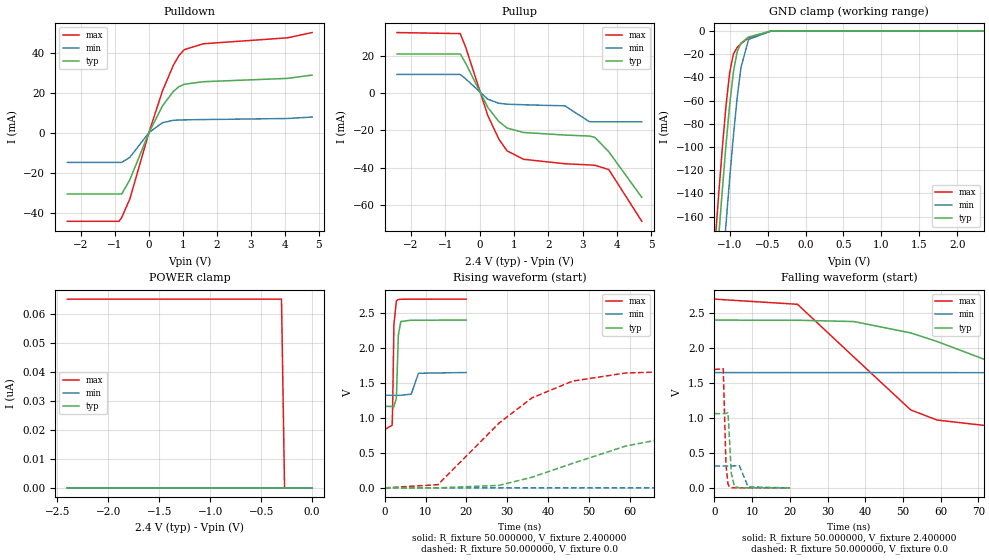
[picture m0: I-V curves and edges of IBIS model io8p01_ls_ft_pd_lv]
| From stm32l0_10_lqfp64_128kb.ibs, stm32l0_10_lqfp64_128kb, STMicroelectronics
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|   Model io8p01_ls_ft_pd_lv
[Model]  io8p01_ls_ft_pd_lv
Model_type I/O
Polarity   Non-Inverting
Enable   Active-Low
Vinl =   0.720000V
Vinh =   1.680000V
Vmeas =  1.200000V
Cref =   50.000000pF
Rref =   100.000000M
Vref =   0.0V
C_comp   4.521100pF   4.438000pF   4.578000pF
[Temperature Range]   25.000000   0.105000k   -40.000000
[Pullup Reference]   2.400000V   1.650000V   2.700000V
[Pulldown Reference]   0.0V   0.0V   0.0V
[POWER Clamp Reference]   2.400000V   1.650000V   2.700000V
[GND Clamp Reference]   0.0V   0.0V   0.0V
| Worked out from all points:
|   slope of the pulldown table from 0 to 0.36 V, typ, clamps not added: 29.5 ohm
|   slope of the pullup table from 0 to 0.36 V, typ, clamps not added: 33.2 ohm
|   GND clamp passes 1 mA (typ) near -0.59 V on its own axis
|   rising waveform, R_fixture 50.000000, V_fixture 2.400000: 20-80 % time 359ps typ, 683ps min, 299ps max; typ from 1.17 V to 2.4 V
|   rising waveform, R_fixture 50.000000, V_fixture 0.0: 20-80 % time 39.5ns typ, 107ns min, 19.4ns max; typ from 0 V to 1.06 V
|   falling waveform, R_fixture 50.000000, V_fixture 2.400000: 20-80 % time 41.1ns typ, 105ns min, 20.5ns max; typ from 2.4 V to 1.17 V
|   falling waveform, R_fixture 50.000000, V_fixture 0.0: 20-80 % time 613ps typ, 981ps min, 509ps max; typ from 1.06 V to 0 V
[Pulldown]
|Voltage   I(typ)   I(min)   I(max)
-2.4V     -30.64mA   -14.84mA   -44.29mA
-880mV    -30.64mA   -14.84mA   -44.29mA
-800mV    -30.64mA   -14.84mA   -42.37mA
-560mV    -23.52mA   -12.34mA   -33.09mA
0V        -765.1nA   -61.09nA   -2.527uA
400mV     13.38mA    4.998mA    20.91mA
720mV     20.62mA    6.178mA    33.69mA
880mV     22.92mA    6.306mA    38.42mA
1.04V     24.19mA    6.384mA    41.49mA
1.6V      25.46mA    6.543mA    44.41mA
4.08V     27.12mA    7.07mA     47.39mA
4.8V      28.77mA    7.815mA    50.01mA
[Pullup]
|Voltage   I(typ)   I(min)   I(max)
-2.4V     21.03mA    10.05mA    32.56mA
-560mV    21.03mA    10.05mA    32mA
-400mV    15.96mA    7.628mA    24.54mA
240mV     -7.653mA   -3.251mA   -12mA
560mV     -15.22mA   -5.43mA    -24.63mA
800mV     -18.73mA   -5.909mA   -31mA
1.28V     -21.13mA   -6.237mA   -35.54mA
2.48V     -22.51mA   -6.819mA   -37.93mA
3.2V      -23.05mA   -15.37mA   -38.57mA
3.36V     -23.83mA   -15.37mA   -38.77mA
3.76V     -31.49mA   -15.37mA   -41.07mA
4.72V     -56mA      -15.37mA   -68.86mA
[GND_clamp]
|Voltage   I(typ)   I(min)   I(max)
-2.4V     -1.379A    -1.445A    -1.35A
-1.2V     -225.9mA   -297.5mA   -189.2mA
-1.15V    -182mA     -253.1mA   -145.3mA
-1.1V     -139.6mA   -209.7mA   -103.5mA
-1.05V    -99.62mA   -167.6mA   -65.7mA
-1V       -63.68mA   -127.3mA   -35.9mA
-950mV    -35mA      -89.93mA   -19.88mA
-900mV    -17.68mA   -57.02mA   -14.13mA
-850mV    -10.5mA    -31.19mA   -11.01mA
-750mV    -5.3mA     -7.337mA   -6.005mA
-450mV    -43.41uA   -101.2uA   -21.28uA
2.35V     52.68uA    50.02uA    36.83uA
[POWER_clamp]
|Voltage   I(typ)   I(min)   I(max)
-2.4V     0A         0A         65.17nA
-300mV    0A         0A         65.17nA
-270mV    0A         0A         0A
0V        0A         0A         0A
[Ramp]
| variable   typ   min   max
dV/dt_r  0.63713/39.40478n   0.18734/0.10657u   1.01518/19.35692n
dV/dt_f  0.74040/41.06525n   0.19260/0.10536u   1.11768/20.45391n
R_load = 50.000000
[Rising Waveform]
R_fixture= 50.000000
V_fixture= 2.400000
V_fixture_min= 1.650000
V_fixture_max= 2.700000
|time   V(typ)   V(min)   V(max)
0s        1.165V     1.324V     836.2mV
1.802ns   1.164V     1.324V     894.6mV
1.922ns   1.163V     1.324V     1.144V
2.242ns   1.159V     1.324V     2.336V
2.843ns   1.284V     1.324V     2.676V
3.323ns   2.182V     1.324V     2.694V
3.924ns   2.379V     1.324V     2.697V
6.486ns   2.398V     1.34V      2.698V
8.248ns   2.398V     1.639V     2.698V
19.94ns   2.399V     1.649V     2.699V
[Rising Waveform]
R_fixture= 50.000000
V_fixture= 0.0
V_fixture_min= 0.0
V_fixture_max= 0.0
|time   V(typ)   V(min)   V(max)
0s        12.97uV    1.645uV    32.24uV
13.01ns   -219uV     -47.07uV   45.21mV
28.03ns   35.46mV    -46.1uV    927.6mV
36.04ns   151mV      -46.74uV   1.286V
46.05ns   350.7mV    -40.58uV   1.527V
59.06ns   598.1mV    -24.06uV   1.643V
87.09ns   914.2mV    1.177mV    1.688V
128.1ns   1.04V      48.28mV    1.692V
255.3ns   1.062V     263.9mV    1.692V
498.5ns   1.062V     312.5mV    1.692V
[Falling Waveform]
R_fixture= 50.000000
V_fixture= 2.400000
V_fixture_min= 1.650000
V_fixture_max= 2.700000
|time   V(typ)   V(min)   V(max)
0s        2.399V     1.649V     2.699V
22.02ns   2.397V     1.648V     2.625V
37.04ns   2.378V     1.648V     1.867V
52.05ns   2.216V     1.648V     1.115V
59.06ns   2.093V     1.648V     969.5mV
72.07ns   1.828V     1.647V     889.9mV
100.1ns   1.382V     1.647V     848.1mV
142.1ns   1.217V     1.63V      837.7mV
283.3ns   1.165V     1.387V     836.2mV
498.5ns   1.165V     1.324V     836.2mV
[Falling Waveform]
R_fixture= 50.000000
V_fixture= 0.0
V_fixture_min= 0.0
V_fixture_max= 0.0
|time   V(typ)   V(min)   V(max)
0s        1.062V     312.5mV    1.692V
2.322ns   1.062V     312.5mV    1.704V
3.043ns   1.064V     312.5mV    334mV
3.564ns   1.076V     312.5mV    60.62mV
3.844ns   837.2mV    312.5mV    24.19mV
4.444ns   214.2mV    312.1mV    3.673mV
5.285ns   18.95mV    315mV      735.3uV
6.607ns   462.4uV    316.8mV    444.6uV
8.929ns   98.08uV    13.37mV    240.5uV
19.94ns   12.97uV    1.645uV    32.24uV
